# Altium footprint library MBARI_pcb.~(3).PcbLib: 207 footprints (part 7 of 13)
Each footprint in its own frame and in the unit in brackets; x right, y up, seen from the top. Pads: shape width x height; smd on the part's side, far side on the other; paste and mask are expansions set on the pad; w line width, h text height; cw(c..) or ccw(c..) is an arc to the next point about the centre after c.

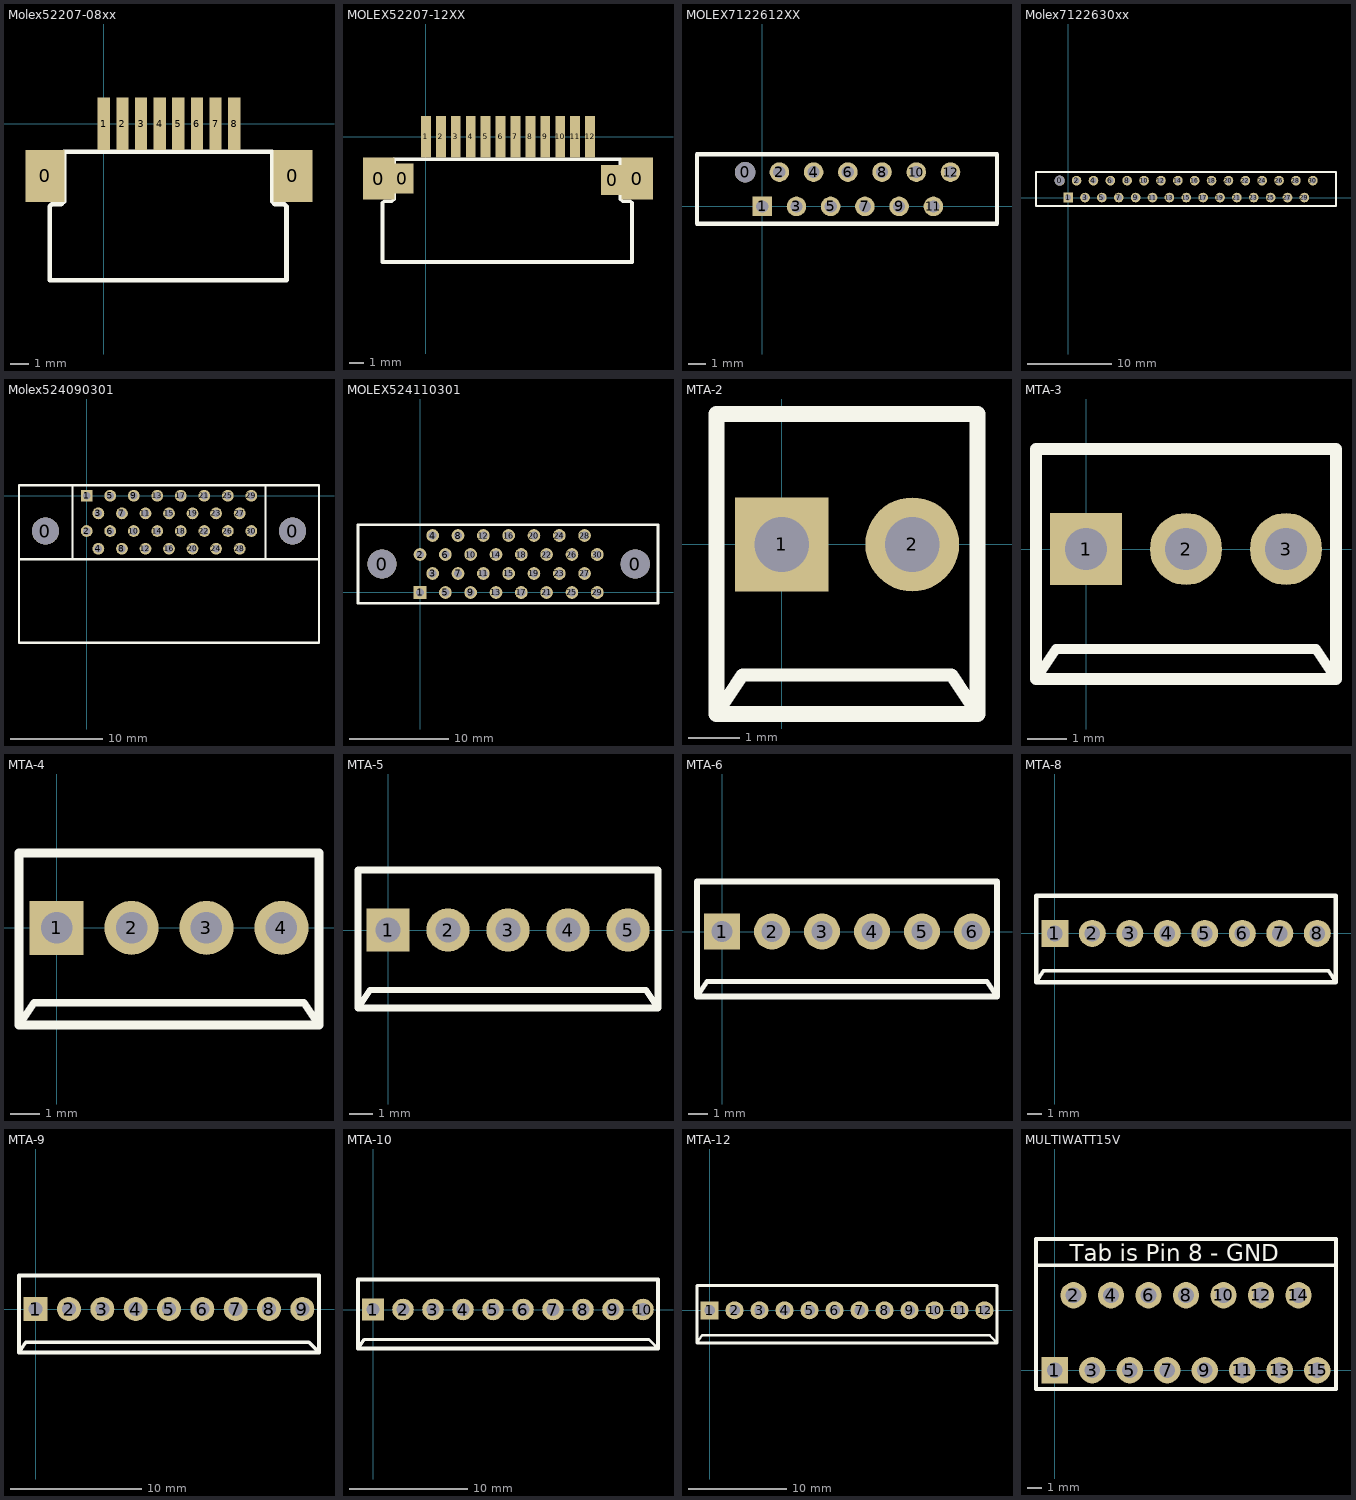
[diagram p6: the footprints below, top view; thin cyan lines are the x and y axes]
## Molex52207-08xx [mm]
pads (10):
  rect 2.1x2.8 smd: 0(-3.15,-2.8) 0(10.15,-2.8)
  rect 0.66x2.8 smd: 1(0,0) 2(1,0) 3(2,0) 4(3,0) 5(4,0) 6(5,0) 7(6,0) 8(7,0)
TopOverlay:
  lines w0.254: -2.9,-8.4 -2.9,-4.424 -2.794,-4.318 -2.286,-4.318 -2.138,-4.17 -2.138,-1.5 9.038,-1.5 9.038,-4.17 9.186,-4.318 9.694,-4.318 9.8,-4.424 9.8,-8.4 -2.9,-8.4

## MOLEX52207-12XX [mm]
pads (16):
  rect 2.1x2.8 smd: 0(-3.15,-2.8) 0(14.15,-2.8)
  rect 1.524x2.032 smd: 0(-1.6,-2.8) 0(12.5,-2.9)
  rect 0.66x2.8 smd: 1(0,0) 2(1,0) 3(2,0) 4(3,0) 5(4,0) 6(5,0) 7(6,0) 8(7,0) 9(8,0) 10(9,0) 11(10,0) 12(11,0)
TopOverlay:
  lines w0.254: -2.9,-8.4 13.8,-8.4 13.8,-4.424 13.694,-4.318 13.186,-4.318 13.038,-4.17 13.038,-1.5 -2.138,-1.5 -2.138,-4.17 -2.286,-4.318 -2.794,-4.318 -2.9,-4.424 -2.9,-8.4

## MOLEX7122612XX [mil]
pads (13):
  round 47 hole 47: 0(-39.37,78.74)
  rect 45x45 hole 28: 1(0,0)
  round 45 hole 28: 2(39.37,78.74) 3(78.74,0) 4(118.11,78.74) 5(157.48,0) 6(196.85,78.74) 7(236.22,0) 8(275.59,78.74) 9(314.96,0) 10(354.33,78.74) 11(393.7,0) 12(433.07,78.74)
TopOverlay:
  lines w10: -150,-40 540,-40 540,120 -150,120 -150,-40

## Molex7122630xx [mil]
pads (31):
  round 47 hole 47: 0(-39.37,78.74)
  rect 45x45 hole 28: 1(0,0)
  round 45 hole 28: 2(39.37,78.74) 3(78.74,0) 4(118.11,78.74) 5(157.48,0) 6(196.85,78.74) 7(236.22,0) 8(275.59,78.74) 9(314.96,0) 10(354.33,78.74) 11(393.7,0) 12(433.07,78.74) 13(472.44,0) 14(511.81,78.74) 15(551.18,0) 16(590.55,78.74) 17(629.92,0) 18(669.29,78.74) 19(708.66,0) 20(748.03,78.74) 21(787.4,0) 22(826.77,78.74) 23(866.14,0) 24(905.51,78.74) 25(944.88,0) 26(984.25,78.74) 27(1023.62,0) 28(1062.99,78.74) 29(1102.36,0) 30(1141.73,78.74)
TopOverlay:
  lines w10: -150,-40 1250,-40 1250,120 -150,120 -150,-40

## Molex524090301 [mil]
pads (32):
  round 115 hole 115: 0(-175,-150) 0(875,-150)
  rect 50x50 hole 32: 1(0,0)
  round 50 hole 32: 2(0,-150) 3(50,-75) 4(50,-225) 5(100,0) 6(100,-150) 7(150,-75) 8(150,-225) 9(200,0) 10(200,-150) 11(250,-75) 12(250,-225) 13(300,0) 14(300,-150) 15(350,-75) 16(350,-225) 17(400,0) 18(400,-150) 19(450,-75) 20(450,-225) 21(500,0) 22(500,-150) 23(550,-75) 24(550,-225) 25(600,0) 26(600,-150) 27(650,-75) 28(650,-225) 29(700,0) 30(700,-150)
TopOverlay:
  lines w10: -287.5,-270 987.5,-270 ; -60,-270 -60,45 ; 760,-270 760,45 ; -287.5,-625 987.5,-625 987.5,45 -287.5,45 -287.5,-625

## MOLEX524110301 [mil]
pads (32):
  round 115 hole 115: 0(-150,112.5) 0(850,112.5)
  rect 50x50 hole 32: 1(0,0)
  round 50 hole 32: 2(0,150) 3(50,75) 4(50,225) 5(100,0) 6(100,150) 7(150,75) 8(150,225) 9(200,0) 10(200,150) 11(250,75) 12(250,225) 13(300,0) 14(300,150) 15(350,75) 16(350,225) 17(400,0) 18(400,150) 19(450,75) 20(450,225) 21(500,0) 22(500,150) 23(550,75) 24(550,225) 25(600,0) 26(600,150) 27(650,75) 28(650,225) 29(700,0) 30(700,150)
TopOverlay:
  lines w10: -245,-42.5 940,-42.5 940,267.5 -245,267.5 -245,-42.5

## MTA-2 [mil]
pads (2):
  rect 72x72 hole 42: 1(0,0)
  round 72 hole 42: 2(100,0)
TopOverlay:
  lines w10: -50,-130 -30,-100 130,-100 150,-130
  lines w12: -50,-130 150,-130 150,100 -50,100 -50,-130

## MTA-3 [mil]
pads (3):
  rect 72x72 hole 42: 1(0,0)
  round 72 hole 42: 2(100,0) 3(200,0)
TopOverlay:
  lines w10: -50,-130 -30,-100 230,-100 250,-130
  lines w12: -50,-130 250,-130 250,100 -50,100 -50,-130

## MTA-4 [mil]
pads (4):
  rect 72x72 hole 42: 1(0,0)
  round 72 hole 42: 2(100,0) 3(200,0) 4(300,0)
TopOverlay:
  lines w10: -50,-130 -30,-100 330,-100 350,-130
  lines w12: -50,-130 -50,100 350,100 350,-130 -50,-130

## MTA-5 [mil]
pads (5):
  rect 72x72 hole 42: 1(0,0)
  round 72 hole 42: 2(100,0) 3(200,0) 4(300,0) 5(400,0)
TopOverlay:
  lines w10: -50,-130 -30,-100 430,-100 450,-130
  lines w12: -50,-130 450,-130 450,100 -50,100 -50,-130

## MTA-6 [mil]
pads (6):
  rect 72x72 hole 42: 1(0,0)
  round 72 hole 42: 2(100,0) 3(200,0) 4(300,0) 5(400,0) 6(500,0)
TopOverlay:
  lines w10: -50,-130 -30,-100 530,-100 550,-130
  lines w12: -50,-130 550,-130 550,100 -50,100 -50,-130

## MTA-8 [mil]
pads (8):
  rect 72x72 hole 42: 1(0,0)
  round 72 hole 42: 2(100,0) 3(200,0) 4(300,0) 5(400,0) 6(500,0) 7(600,0) 8(700,0)
TopOverlay:
  lines w10: -50,-130 -30,-100 730,-100 750,-130
  lines w12: -50,-130 -50,100 750,100 750,-130 -50,-130

## MTA-9 [mil]
pads (9):
  rect 72x72 hole 42: 1(0,0)
  round 72 hole 42: 2(100,0) 3(200,0) 4(300,0) 5(400,0) 6(500,0) 7(600,0) 8(700,0) 9(800,0)
TopOverlay:
  lines w10: -50,-130 -30,-100 820,-100 850,-130
  lines w12: -50,-130 850,-130 850,100 -50,100 -50,-130

## MTA-10 [mil]
pads (10):
  rect 72x72 hole 42: 1(0,0)
  round 72 hole 42: 2(100,0) 3(200,0) 4(300,0) 5(400,0) 6(500,0) 7(600,0) 8(700,0) 9(800,0) 10(900,0)
TopOverlay:
  lines w10: -50,-130 -30,-100 920,-100 950,-130
  lines w12: -50,-130 950,-130 950,100 -50,100 -50,-130

## MTA-12 [mil]
pads (12):
  rect 72x72 hole 42: 1(0,0)
  round 72 hole 42: 2(100,0) 3(200,0) 4(300,0) 5(400,0) 6(500,0) 7(600,0) 8(700,0) 9(800,0) 10(900,0) 11(1000,0) 12(1100,0)
TopOverlay:
  lines w10: -50,-130 -30,-100 1120,-100 1150,-130
  lines w12: -50,-130 1150,-130 1150,100 -50,100 -50,-130

## MULTIWATT15V [mil]
pads (15):
  rect 70x70 hole 42: 1(0,0)
  round 70 hole 42: 2(50,200) 3(100,0) 4(150,200) 5(200,0) 6(250,200) 7(300,0) 8(350,200) 9(400,0) 10(450,200) 11(500,0) 12(550,200) 13(600,0) 14(650,200) 15(700,0)
TopOverlay:
  lines w10: -50,280 750,280 ; -50,-50 750,-50 750,350 -50,350 -50,-50
  text "Tab is Pin 8 - GND" at 40,290 h45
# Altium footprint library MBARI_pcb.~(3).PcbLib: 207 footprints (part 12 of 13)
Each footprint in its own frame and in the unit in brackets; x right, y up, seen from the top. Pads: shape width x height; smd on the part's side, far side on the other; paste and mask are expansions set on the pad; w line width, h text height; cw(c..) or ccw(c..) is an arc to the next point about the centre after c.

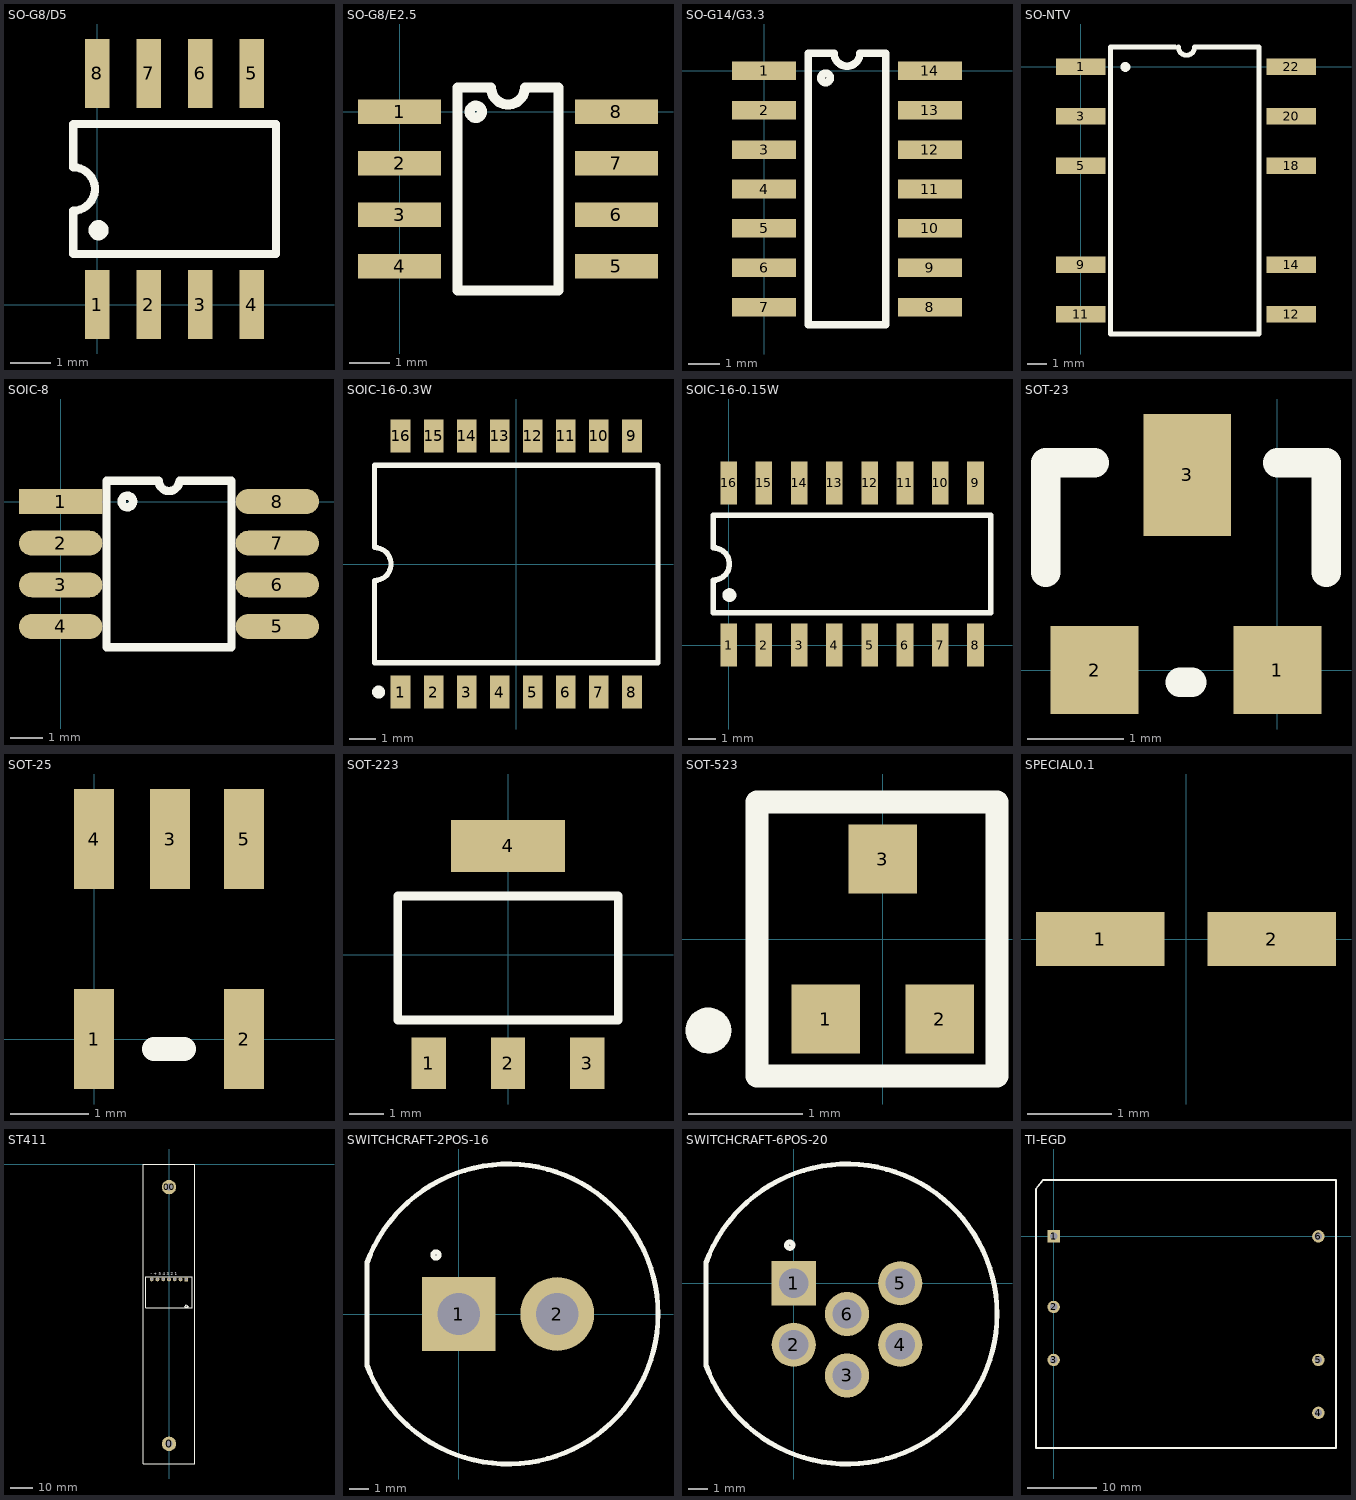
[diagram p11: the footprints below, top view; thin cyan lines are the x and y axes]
## SO-G8/D5 [mm]
pads (8):
  rect 0.6x1.7 smd: 1(0,0) 2(1.27,0) 3(2.54,0) 4(3.81,0) 5(3.81,5.7) 6(2.54,5.7) 7(1.27,5.7) 8(0,5.7)
TopOverlay:
  circle w0.25: c0.027,1.834 r0.125
  lines w0.2: -0.595,2.317 ccw(c-0.595,2.85) -0.595,3.383 -0.595,4.45 4.405,4.45 4.405,1.25 -0.595,1.25 -0.595,2.317

## SO-G8/E2.5 [mm]
pads (8):
  rect 2.05x0.6 smd: 1(0,0) 2(0,-1.27) 3(0,-2.54) 4(0,-3.81) 5(5.35,-3.81) 6(5.35,-2.54) 7(5.35,-1.27) 8(5.35,0)
TopOverlay:
  circle w0.25: c1.882,0 r0.15
  lines w0.25: 2.258,0.595 1.425,0.595 1.425,-4.405 3.925,-4.405 3.925,0.595 3.092,0.595 cw(c2.675,0.595) 2.258,0.595

## SO-G14/G3.3 [mm]
pads (14):
  rect 2.05x0.6 smd: 1(0,0) 2(0,-1.27) 3(0,-2.54) 4(0,-3.81) 5(0,-5.08) 6(0,-6.35) 7(0,-7.62) 8(5.35,-7.62) 9(5.35,-6.35) 10(5.35,-5.08) 11(5.35,-3.81) 12(5.35,-2.54) 13(5.35,-1.27) 14(5.35,0)
TopOverlay:
  circle w0.25: c1.984,-0.229 r0.15
  lines w0.25: 1.425,-8.185 1.425,0.565 2.258,0.565 ccw(c2.675,0.565) 3.092,0.565 3.925,0.565 3.925,-8.185 1.425,-8.185

## SO-NTV [mm]
pads (10):
  rect 2.54x0.85 smd: 1(0,0) 3(0,-2.54) 5(0,-5.08) 9(0,-10.16) 11(0,-12.7) 12(10.8,-12.7) 14(10.8,-10.16) 18(10.8,-5.08) 20(10.8,-2.54) 22(10.8,0)
TopOverlay:
  circle w0.254: c2.286,0 r0.127
  lines w0.25: 5.009,1.016 ccw(c5.425,1.016) 5.842,1.016
  lines w0.254: 4.826,1.016 1.524,1.016 1.524,-13.716 9.144,-13.716 9.144,1.016 5.842,1.016

## SOIC-8 [mil]
pads (8):
  rect 100x30 smd: 1(0,0)
  oval 100x30 smd: 2(0,-50) 3(0,-100) 4(0,-150) 5(260,-150) 6(260,-100) 7(260,-50) 8(260,0)
TopOverlay:
  circle w10: c80,0 r7
  lines w10: 55,-175 55,25 117.5,25 ccw(c130,25) 142.5,25 205,25 205,-175 55,-175

## SOIC-16-0.3W [mil] "LTC SW pkg DWG# 05-08-1620"
height 100
pads (16):
  rect 30x50 smd: 1(-175,-193.9) 2(-125,-193.9) 3(-75,-193.9) 4(-25,-193.9) 5(25,-193.9) 6(75,-193.9) 7(125,-193.9) 8(175,-193.9) 9(175,193.9) 10(125,193.9) 11(75,193.9) 12(25,193.9) 13(-25,193.9) 14(-75,193.9) 15(-125,193.9) 16(-175,193.9)
TopOverlay:
  circle w9.84: c-208.46,-193.9 r4.92
  lines w7.87: -214.57,-149.61 214.57,-149.61 214.57,149.61 -214.57,149.61 -214.57,25 cw(c-214.57,0) -214.57,-25 -214.57,-149.61

## SOIC-16-0.15W [mm] "SOIC-16 0.15\"Wide 1.27mm Pitch"
height 1.524
pads (16):
  rect 0.6x1.55 smd: 1(0,0) 2(1.27,0) 3(2.54,0) 4(3.81,0) 5(5.08,0) 6(6.35,0) 7(7.62,0) 8(8.89,0) 9(8.89,5.85) 10(7.62,5.85) 11(6.35,5.85) 12(5.08,5.85) 13(3.81,5.85) 14(2.54,5.85) 15(1.27,5.85) 16(0,5.85)
TopOverlay:
  circle w0.25: c0.027,1.803 r0.125
  lines w0.2: -0.555,1.175 9.445,1.175 9.445,4.675 -0.555,4.675 -0.555,3.508 cw(c-0.555,2.925) -0.555,2.342 -0.555,1.175

## SOT-23 [mil]
pads (3):
  rect 36x36 smd: 1(0,0) 2(-75,0)
  rect 36x50 smd: 3(-37,80)
TopOverlay:
  lines w12: -95,40 -95,85 -75,85 ; -40,-5 -35,-5 ; 0,85 20,85 20,40

## SOT-25 [mil]
pads (5):
  rect 20x50 smd: 1(0,0) 2(75,0) 3(38,100) 4(0,100) 5(75,100)
TopOverlay:
  lines w12: 30,-5 45,-5

## SOT-223 [mm] "4 lead SMD NS:MP04A"
height 1.6
pads (4):
  rect 1x1.5 smd: 1(-2.3,-3.15) 2(0,-3.15) 3(2.3,-3.15)
  rect 3.3x1.5 smd: 4(0,3.15)
TopOverlay:
  lines w0.254: -3.2,-1.9 3.2,-1.9 3.2,1.7 -3.2,1.7 -3.2,-1.9

## SOT-523 [mm] "Diodes Inc SOT-523"
pads (3):
  rect 0.6x0.6 smd: 1(-0.5,-0.7) 2(0.5,-0.7) 3(0,0.7)
TopOverlay:
  circle w0.2: c-1.525,-0.8 r0.1
  lines w0.2: -1.1,-1.2 -1.1,1.2 1,1.2 1,-1.2 -1.1,-1.2

## SPECIAL0.1 [mil]
pads (2):
  rect 60x25 smd: 1(-40,0) 2(40,0)

## ST411 [mil]
pads (9):
  round 250 hole 125: 0(0,-4850) 00(0,-400)
  rect 66x66 hole 42: 1(300,-2000)
  round 66 hole 42: 2(200,-2000) 3(100,-2000) 4(0,-2000) 5(-100,-2000) 6(-200,-2000) 7(-300,-2000)
TopOverlay:
  lines w10: -450,-5200 -450,-700 -450,0 450,0 450,-5200 -450,-5200 ; -400,-2490 -400,-1950 400,-1950 400,-2490 -400,-2490 ; 271.71,-2471.71 331.71,-2471.71 301.71,-2441.71 271.71,-2471.71
  text "- + 5 4 3 2 1" at -320,-1930 h51

## SWITCHCRAFT-2POS-16 [mil]
pads (2):
  rect 150x150 hole 86: 1(0,0)
  round 150 hole 86: 2(200,0)
TopOverlay:
  circle w10: c-46.4,120 r6.4
  lines w10: -186.61,-104.32 ccw(c100,0) -186.61,104.32 -186.61,-104.32

## SWITCHCRAFT-6POS-20 [mil]
pads (6):
  rect 90x90 hole 59.5: 1(0,0)
  round 90 hole 59.5: 2(0,-125) 3(108.25,-187.5) 4(216.51,-125) 5(216.51,0) 6(108.25,-62.5)
TopOverlay:
  circle w10: c-8.15,77.5 r6.4
  lines w10: -178.35,-166.82 ccw(c108.25,-62.5) -178.35,41.82 -178.35,-166.82

## TI-EGD [mil] "TI Powertrends EGD package for isol DC->DC converters"
height 330
pads (6):
  rect 70x70 hole 42: 1(0,0)
  round 70 hole 42: 2(0,-400) 3(0,-700) 4(1500,-1000) 5(1500,-700) 6(1500,0)
TopOverlay:
  lines w10: -100,-1200 -100,270 -60,320 1600,320 1600,-1200 -100,-1200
